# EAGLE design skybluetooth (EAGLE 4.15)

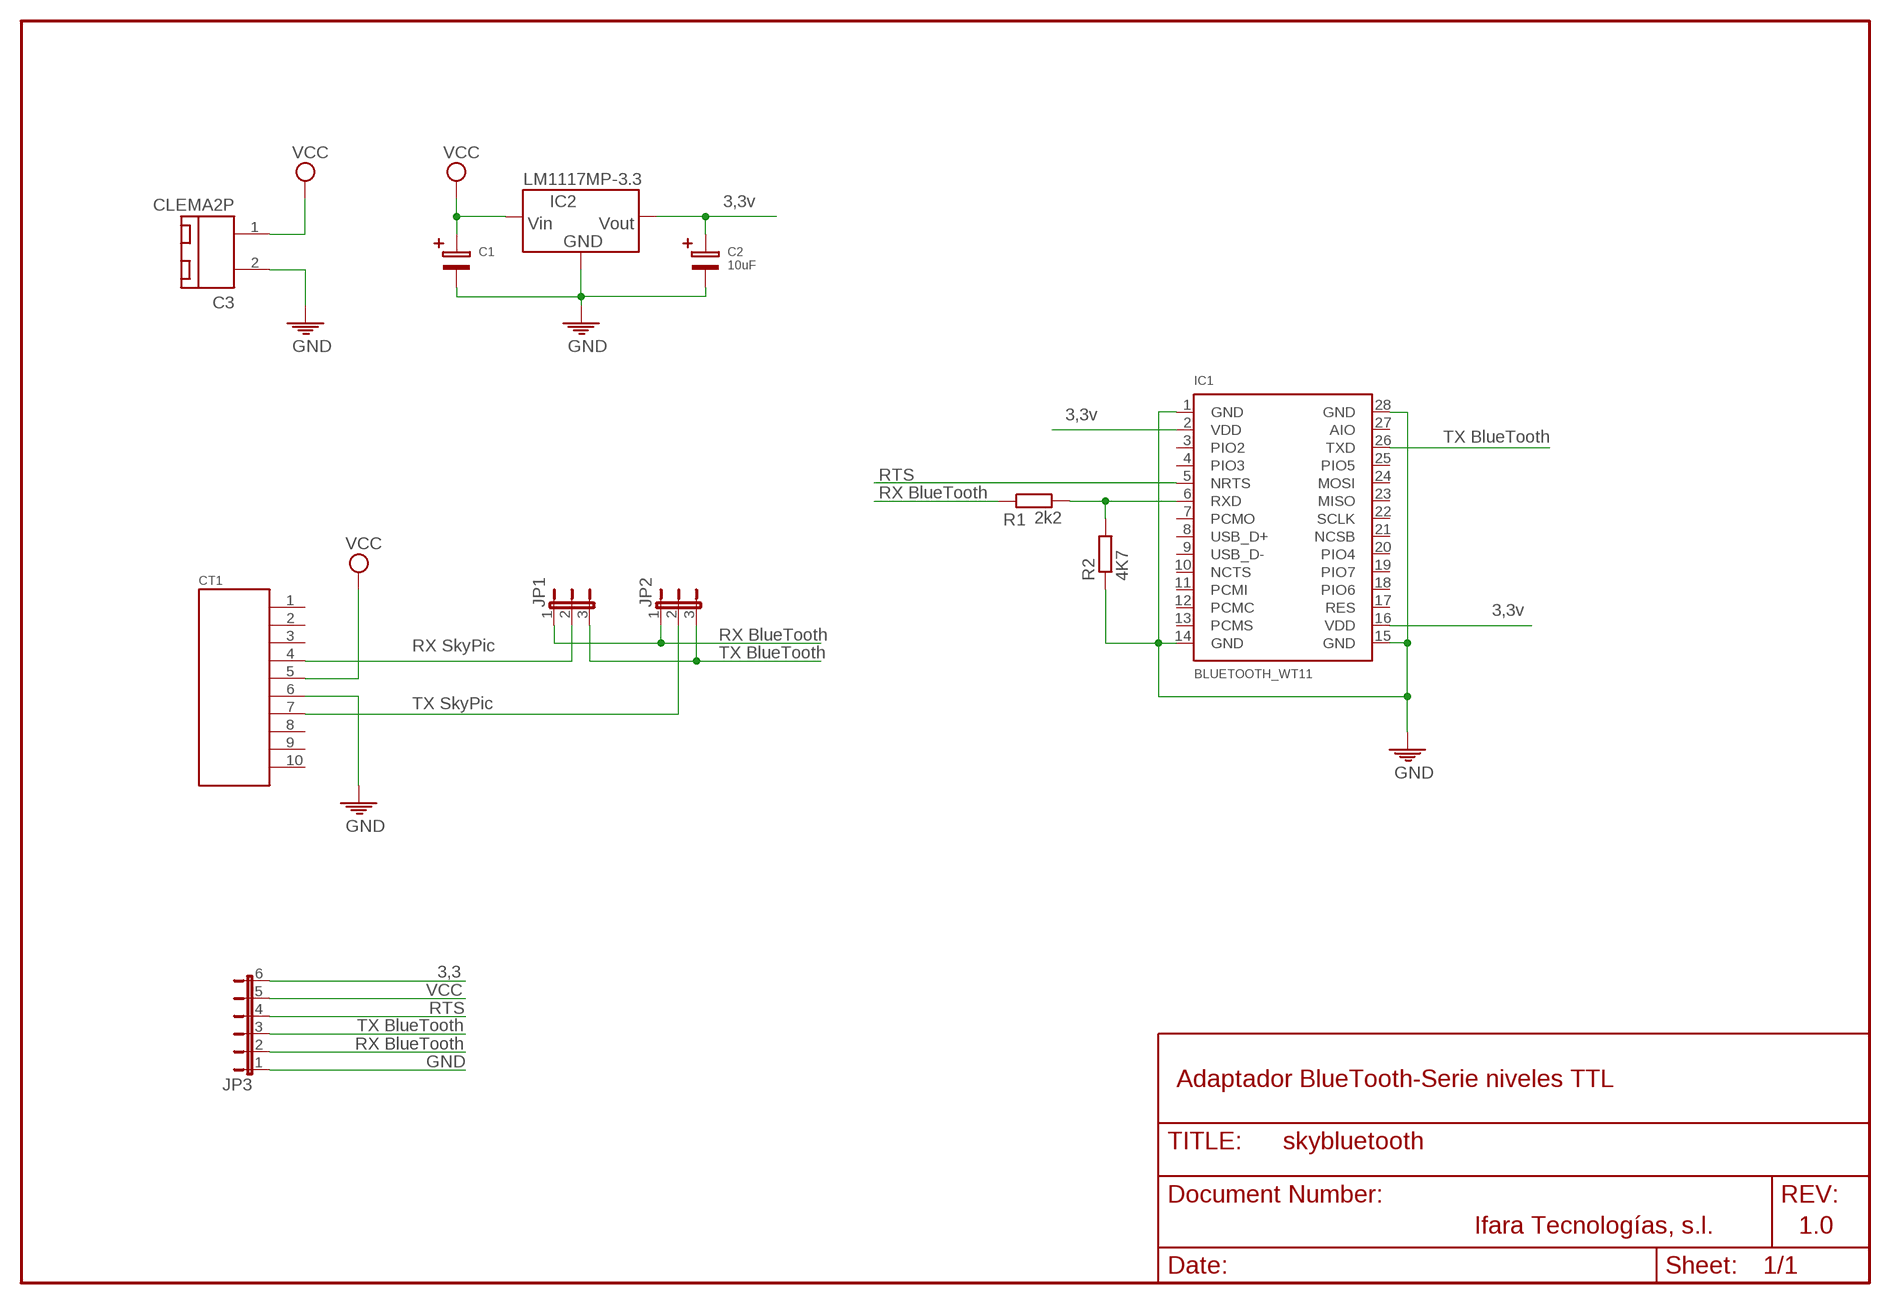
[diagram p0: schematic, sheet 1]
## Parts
C1  CON-ELE-2.5  [C2]
C2  10uF  CON-ELE-2.5  [C2]
C3  CLEMA2P  [C2P]
CT1  CTCONA  [CTCON]
IC1  BLUETOOTH_WT11  [BLUETOOTH1]
IC2  LM1117MP-3.3  [SOT223]
JP1  JUMPER3R  [JP3R]
JP2  JUMPER3R  [JP3R]
JP3  JUMPER6R  [1X06]
R1  2k2  RESISTENCIA-R0805  [R0805]
R2  4K7  RESISTENCIA-R0805  [R0805]

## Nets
3,3V: C2.P$1 IC1.2(VDD) IC1.16(VDD) IC2.2(VOUT) JP3.6
GND: C1.P$2 C2.P$2 C3.2 CT1.6 IC1.1(GND) IC1.14(GND) IC1.15(GND) IC1.28(GND) IC2.1(GND) JP3.1 R2.1
N$1: IC1.6(RXD) R1.2 R2.2
N$2: CT1.4 JP1.2
N$3: CT1.7 JP2.2
RTS: IC1.5(NRTS) JP3.4
RX_BT: JP1.1 JP2.1 JP3.2 R1.1
TX_BT: IC1.26(TXD) JP1.3 JP2.3 JP3.3
VCC: C1.P$1 C3.1 CT1.5 IC2.3(VIN) JP3.5
Unconnected: CT1.1 CT1.2 CT1.3 CT1.8 CT1.9 CT1.10 IC1.3(PIO2) IC1.4(PIO3) IC1.7(PCMO) IC1.8(USB_D+) IC1.9(USB_D-) IC1.10(NCTS) IC1.11(PCMI) IC1.12(PCMC) IC1.13(PCMS) IC1.17(RES) IC1.18(PIO6) IC1.19(PIO7) IC1.20(PIO4) IC1.21(NCSB) IC1.22(SCLK) IC1.23(MISO) IC1.24(MOSI) IC1.25(PIO5) IC1.27(AIO)

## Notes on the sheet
- 3,3v
- 3,3v
- TX BlueTooth
- RTS
- RX BlueTooth
- 3,3v
- RX BlueTooth
- RX SkyPic
- TX BlueTooth
- TX SkyPic
- 3,3
- VCC
- RTS
- TX BlueTooth
- RX BlueTooth
- GND
- Adaptador BlueTooth-Serie niveles TTL
- Ifara Tecnologías, s.l. | 1.0

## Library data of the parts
C1 C2 = ifara2006:CON-ELE
C3 = ifara2006:CLEMA2: Clema doble
CT1 = ifara2006:CTCON: Conector compatible CT
IC1 = ifara2006:BLUETOOTH_WT11
IC2 = ifara2006:LM1117MP-3.3
JP1 JP2 = ifara2006:JUMPER3: jumper triple
JP3 = ifara2006:JUMPER6
R1 R2 = ifara2006:RESISTENCIA: Resistencia de paso 10mm

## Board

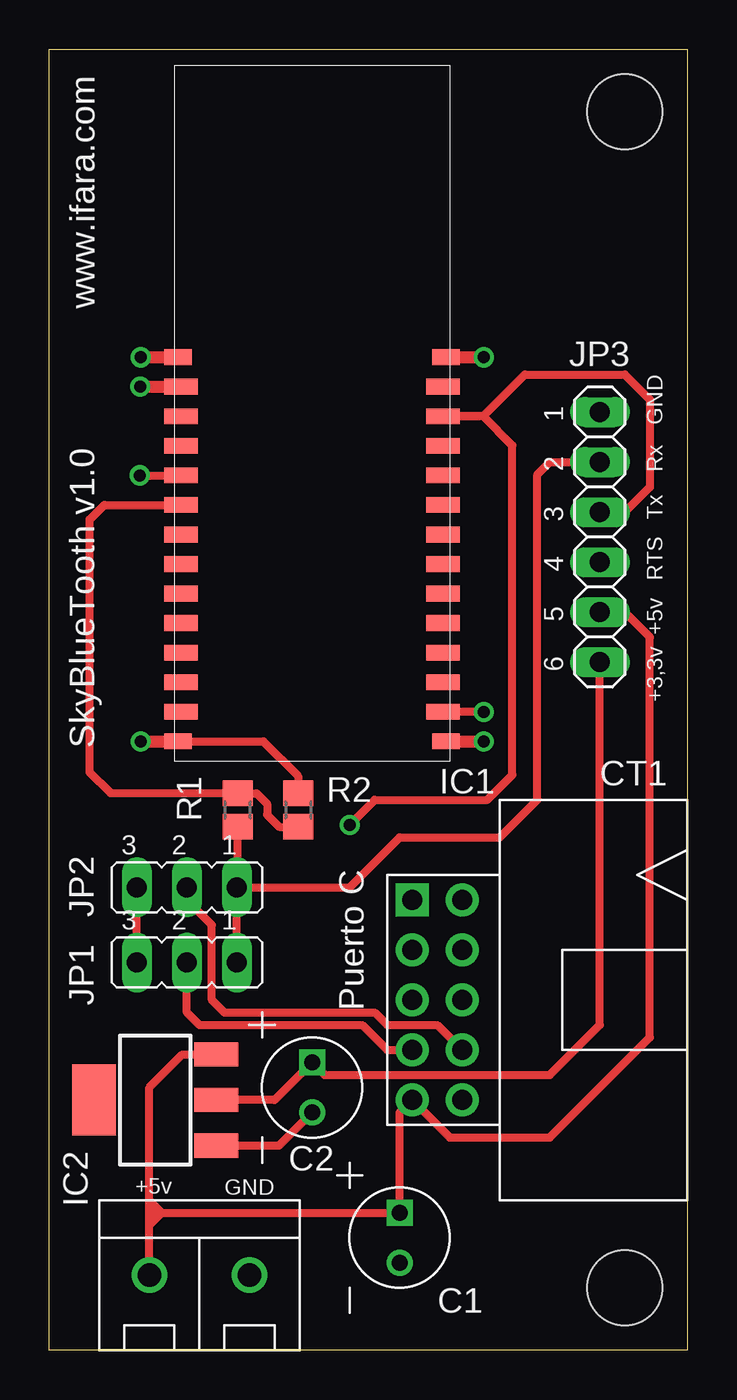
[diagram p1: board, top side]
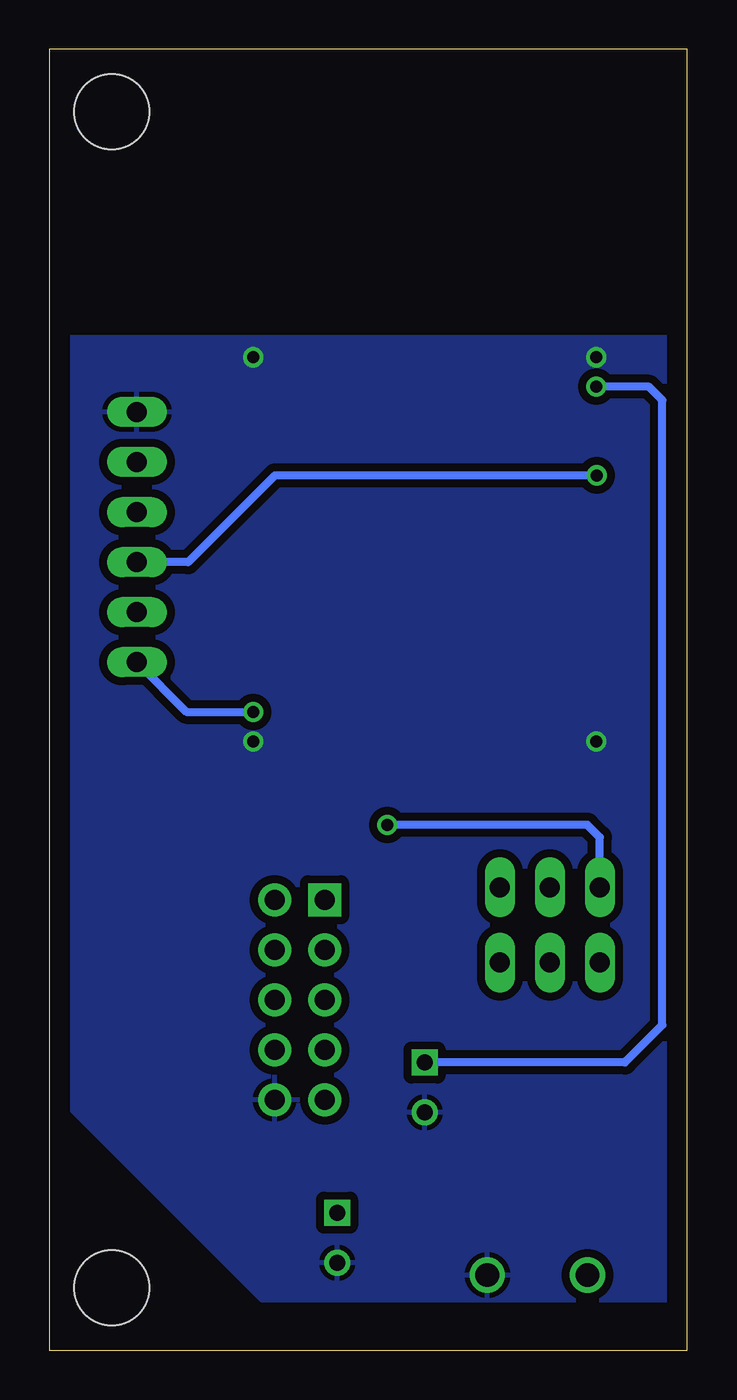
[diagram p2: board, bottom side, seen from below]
Size 32.38 x 66.04 mm. Coordinates in mm from the lower left corner, seen from the top.
Outline: 0,0 0,66.04 32.38,66.04 32.38,0 0,0
Copper layers (1*16): Top 0.035mm / dielectric 1.5mm / Bottom 0.035mm
Design rules "default": minimum track width 10mil, minimum drill 24mil, track to track 8mil, track to pad 8mil, pad to pad 8mil, via to via 8mil, smd to smd 8mil, copper to edge 40mil, drill to drill 8mil, minimum pad ring 10mil, minimum via ring 8mil, stop-mask expansion 4mil, vias tented up to drill 0mil, thermal gap 10mil
Holes 3.81 mm at 29.21,3.17 29.21,62.87

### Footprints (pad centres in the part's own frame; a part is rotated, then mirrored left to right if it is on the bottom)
C2 = drill 0.813 square: P$1 0,0 | drill 0.813 round: P$2 2.54,0
C2P = drill 1.2 pad 1.676 round: 1 0,0; 2 5.08,0
CTCON = drill 1.016 pad 1.676 square: 1 0,0 | drill 1.016 pad 1.676 round: 2 2.54,0; 3 5.08,0; 4 7.62,0; 5 10.16,0; 6 10.16,2.54; 7 7.62,2.54; 8 5.08,2.54; 9 2.54,2.54; 10 0,2.54
BLUETOOTH1 = smd 0.8 x 1.4: 1 8.5,6.8; 14 -11,6.8; 15 -11,-6.8; 28 8.5,-6.8 | smd 0.8 x 1.7: 2 7,6.65; 3 5.5,6.65; 4 4,6.65; 5 2.5,6.65; 6 1,6.65; 7 -0.5,6.65; 8 -2,6.65; 9 -3.5,6.65; 10 -5,6.65; 11 -6.5,6.65; 12 -8,6.65; 13 -9.5,6.65; 16 -9.5,-6.65; 17 -8,-6.65; 18 -6.5,-6.65; 19 -5,-6.65; 20 -3.5,-6.65; 21 -2,-6.65; 22 -0.5,-6.65; 23 1,-6.65; 24 2.5,-6.65; 25 4,-6.65; 26 5.5,-6.65; 27 7,-6.65
SOT223 = smd 1.219 x 2.235: 1 -2.311,-3.099; 2 0,-3.099; 3 2.311,-3.099 | smd 3.6 x 2.2: 4 0,3.099
JP3R = drill 1.016 long: 1 0,0; 2 2.54,0; 3 5.08,0
1X06 = drill 1.016 long: 1 0,0; 2 2.54,0; 3 5.08,0; 4 7.62,0; 5 10.16,0; 6 12.7,0
R0805 = smd 1.3 x 1.5: 1 -0.85,0; 2 0.85,0

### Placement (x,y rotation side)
C1  17.78,6.99 270 top
C2  13.34,14.61 270 top
C3  5.08,3.81 0 top
CT1  18.41,22.86 270 top
IC1  13.34,41.91 90 top
IC2  5.38,12.7 90 top
JP1  9.53,19.68 180 top
JP2  9.53,23.5 180 top
JP3  27.94,47.62 270 top
R1  9.56,27.42 90 top
R2  12.63,27.42 270 top

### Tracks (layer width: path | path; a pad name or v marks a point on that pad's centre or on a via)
3,3V  (via drill 0.61)
  Top 0.406: IC2.2 11.43,12.7 C2.P$1 13.97,13.97 25.4,13.97 27.94,16.51 JP3.6 | v4.63,48.91 | v4.63,48.91 | v4.63,48.91 | v22.04,32.41 | v22.04,32.41 | IC1.16 v22.04,32.41
  Top 0.61: v4.63,48.91 IC1.2
  Bottom 0.406: C2.P$1 3.17,14.61 1.27,16.51 1.27,48.22 1.96,48.91 v4.63,48.91 | v22.04,32.41 25.42,32.41 JP3.6
GND  (via drill 0.61)
  Top 0.406: IC2.1 11.66,10.39 C2.P$2 | IC1.14 10.87,30.91 12.63,29.15 R2.1
  Top 0.61: IC1.14 v4.63,30.91 v4.63,30.9 | v4.63,50.4 | IC1.1 v4.63,50.41 v4.63,50.4 | v22.04,50.4 | IC1.28 v22.04,50.41 v22.04,50.4 | v22.04,30.9 | IC1.15 v22.04,30.91 v22.04,30.9
  pour Bottom (isolate 0.406): 0.64,2.54 21.59,2.54 31.75,12.7 31.75,51.44 0.64,51.44
N$1
  Top 0.406: R2.2 | R2.2 | R2.2 11.67,26.57 11.05,27.18 11.05,27.74 10.52,28.27 R1.2 | IC1.6 2.79,42.91 2.05,42.17 2.05,29.33 3.11,28.28 R1.2 | R1.2
N$2
  Top 0.406: JP1.2 6.99,17.14 7.62,16.51 15.88,16.51 17.14,15.24 CT1.4
N$3
  Top 0.406: JP2.2 6.99,22.86 8.25,21.59 8.25,17.78 8.89,17.14 16.51,17.14 17.14,16.51 19.68,16.51 CT1.7
RTS  (via drill 0.61)
  Top 0.406: v4.6,44.41 | IC1.5 v4.6,44.41
  Bottom 0.406: JP3.4 25.34,40.01 20.94,44.41 v4.6,44.41 | v4.6,44.41
RX_BT
  Top 0.406: JP1.1 JP2.1 | R1.1 9.56,23.53 JP2.1 | JP3.2 25.4,45.09 24.77,44.45 24.77,27.94 22.86,26.04 17.78,26.04 15.24,23.5 JP2.1
TX_BT  (via drill 0.61)
  Top 0.406: JP1.3 JP2.3 | 22.01,47.41 IC1.26 21.8,47.41 | 22.01,47.41 24.13,49.53 29.21,49.53 30.48,48.26 30.48,43.81 29.21,42.55 JP3.3 | v15.24,26.67 16.51,27.94 22.22,27.94 23.49,29.21 23.49,45.92 22.01,47.41 | 22.01,47.41
  Bottom 0.406: JP2.3 4.45,26.04 5.08,26.67 v15.24,26.67
VCC
  Top 0.406: IC2.3 6.76,15.01 5.08,13.34 5.08,7.62 | C3.1 5.08,6.35 | 5.08,6.35 5.08,6.99 | 5.08,6.99 5.08,7.62 | 5.08,6.99 5.71,6.99 | 5.71,6.99 C1.P$1 17.78,12.06 CT1.5 20.32,10.79 25.4,10.79 30.48,15.88 30.48,36.2 29.21,37.47 JP3.5 | 5.08,6.35 5.08,7.62 | 5.08,6.35 5.71,6.99 | 5.08,7.62 5.71,6.99

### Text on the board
tPlace: www.ifara.com | SkyBlueTooth v1.0 | Puerto C
tNames: GND | Rx | Tx | RTS | +5v | +3,3v | IC1 | +5v | GND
